VERSION 5.7 ;
  NOWIREEXTENSIONATPIN ON ;
  DIVIDERCHAR "/" ;
  BUSBITCHARS "[]" ;
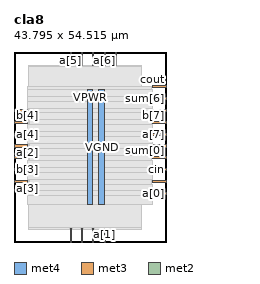
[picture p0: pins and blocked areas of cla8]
MACRO cla8
  CLASS BLOCK ;
  FOREIGN cla8 ;
  ORIGIN 0.000 0.000 ;
  SIZE 43.795 BY 54.515 ;
  PIN VGND
    DIRECTION INOUT ;
    USE GROUND ;
    PORT
      LAYER met4 ;
        RECT 24.340 10.640 25.940 43.760 ;
    END
  END VGND
  PIN VPWR
    DIRECTION INOUT ;
    USE POWER ;
    PORT
      LAYER met4 ;
        RECT 21.040 10.640 22.640 43.760 ;
    END
  END VPWR
  PIN a[0]
    DIRECTION INPUT ;
    USE SIGNAL ;
    ANTENNAGATEAREA 0.196500 ;
    PORT
      LAYER met3 ;
        RECT 39.795 13.640 43.795 14.240 ;
    END
  END a[0]
  PIN a[1]
    DIRECTION INPUT ;
    USE SIGNAL ;
    ANTENNAGATEAREA 0.196500 ;
    PORT
      LAYER met2 ;
        RECT 25.850 0.000 26.130 4.000 ;
    END
  END a[1]
  PIN a[2]
    DIRECTION INPUT ;
    USE SIGNAL ;
    ANTENNAGATEAREA 0.196500 ;
    PORT
      LAYER met3 ;
        RECT 0.000 27.240 4.000 27.840 ;
    END
  END a[2]
  PIN a[3]
    DIRECTION INPUT ;
    USE SIGNAL ;
    ANTENNAGATEAREA 0.196500 ;
    PORT
      LAYER met3 ;
        RECT 0.000 17.040 4.000 17.640 ;
    END
  END a[3]
  PIN a[4]
    DIRECTION INPUT ;
    USE SIGNAL ;
    ANTENNAGATEAREA 0.196500 ;
    PORT
      LAYER met3 ;
        RECT 0.000 30.640 4.000 31.240 ;
    END
  END a[4]
  PIN a[5]
    DIRECTION INPUT ;
    USE SIGNAL ;
    ANTENNAGATEAREA 0.196500 ;
    PORT
      LAYER met2 ;
        RECT 16.190 50.515 16.470 54.515 ;
    END
  END a[5]
  PIN a[6]
    DIRECTION INPUT ;
    USE SIGNAL ;
    ANTENNAGATEAREA 0.196500 ;
    PORT
      LAYER met2 ;
        RECT 25.850 50.515 26.130 54.515 ;
    END
  END a[6]
  PIN a[7]
    DIRECTION INPUT ;
    USE SIGNAL ;
    ANTENNAGATEAREA 0.196500 ;
    PORT
      LAYER met3 ;
        RECT 39.795 30.640 43.795 31.240 ;
    END
  END a[7]
  PIN b[0]
    DIRECTION INPUT ;
    USE SIGNAL ;
    ANTENNAGATEAREA 0.196500 ;
    PORT
      LAYER met3 ;
        RECT 39.795 17.040 43.795 17.640 ;
    END
  END b[0]
  PIN b[1]
    DIRECTION INPUT ;
    USE SIGNAL ;
    ANTENNAGATEAREA 0.196500 ;
    PORT
      LAYER met2 ;
        RECT 22.630 0.000 22.910 4.000 ;
    END
  END b[1]
  PIN b[2]
    DIRECTION INPUT ;
    USE SIGNAL ;
    ANTENNAGATEAREA 0.196500 ;
    PORT
      LAYER met3 ;
        RECT 0.000 23.840 4.000 24.440 ;
    END
  END b[2]
  PIN b[3]
    DIRECTION INPUT ;
    USE SIGNAL ;
    ANTENNAGATEAREA 0.196500 ;
    PORT
      LAYER met3 ;
        RECT 0.000 20.440 4.000 21.040 ;
    END
  END b[3]
  PIN b[4]
    DIRECTION INPUT ;
    USE SIGNAL ;
    ANTENNAGATEAREA 0.196500 ;
    PORT
      LAYER met3 ;
        RECT 0.000 34.040 4.000 34.640 ;
    END
  END b[4]
  PIN b[5]
    DIRECTION INPUT ;
    USE SIGNAL ;
    ANTENNAGATEAREA 0.196500 ;
    PORT
      LAYER met2 ;
        RECT 19.410 50.515 19.690 54.515 ;
    END
  END b[5]
  PIN b[6]
    DIRECTION INPUT ;
    USE SIGNAL ;
    ANTENNAGATEAREA 0.196500 ;
    PORT
      LAYER met2 ;
        RECT 29.070 50.515 29.350 54.515 ;
    END
  END b[6]
  PIN b[7]
    DIRECTION INPUT ;
    USE SIGNAL ;
    ANTENNAGATEAREA 0.196500 ;
    PORT
      LAYER met3 ;
        RECT 39.795 34.040 43.795 34.640 ;
    END
  END b[7]
  PIN cin
    DIRECTION INPUT ;
    USE SIGNAL ;
    ANTENNAGATEAREA 0.196500 ;
    PORT
      LAYER met3 ;
        RECT 39.795 20.440 43.795 21.040 ;
    END
  END cin
  PIN cout
    DIRECTION OUTPUT ;
    USE SIGNAL ;
    ANTENNADIFFAREA 0.445500 ;
    PORT
      LAYER met3 ;
        RECT 39.795 44.240 43.795 44.840 ;
    END
  END cout
  PIN sum[0]
    DIRECTION OUTPUT ;
    USE SIGNAL ;
    ANTENNADIFFAREA 0.445500 ;
    PORT
      LAYER met3 ;
        RECT 39.795 23.840 43.795 24.440 ;
    END
  END sum[0]
  PIN sum[1]
    DIRECTION OUTPUT ;
    USE SIGNAL ;
    ANTENNADIFFAREA 0.445500 ;
    PORT
      LAYER met3 ;
        RECT 39.795 27.240 43.795 27.840 ;
    END
  END sum[1]
  PIN sum[2]
    DIRECTION OUTPUT ;
    USE SIGNAL ;
    ANTENNADIFFAREA 0.445500 ;
    PORT
      LAYER met2 ;
        RECT 19.410 0.000 19.690 4.000 ;
    END
  END sum[2]
  PIN sum[3]
    DIRECTION OUTPUT ;
    USE SIGNAL ;
    ANTENNADIFFAREA 0.445500 ;
    PORT
      LAYER met2 ;
        RECT 16.190 0.000 16.470 4.000 ;
    END
  END sum[3]
  PIN sum[4]
    DIRECTION OUTPUT ;
    USE SIGNAL ;
    ANTENNADIFFAREA 0.445500 ;
    PORT
      LAYER met3 ;
        RECT 0.000 37.440 4.000 38.040 ;
    END
  END sum[4]
  PIN sum[5]
    DIRECTION OUTPUT ;
    USE SIGNAL ;
    ANTENNADIFFAREA 0.445500 ;
    PORT
      LAYER met2 ;
        RECT 22.630 50.515 22.910 54.515 ;
    END
  END sum[5]
  PIN sum[6]
    DIRECTION OUTPUT ;
    USE SIGNAL ;
    ANTENNADIFFAREA 0.445500 ;
    PORT
      LAYER met3 ;
        RECT 39.795 40.840 43.795 41.440 ;
    END
  END sum[6]
  PIN sum[7]
    DIRECTION OUTPUT ;
    USE SIGNAL ;
    ANTENNADIFFAREA 0.445500 ;
    PORT
      LAYER met3 ;
        RECT 39.795 37.440 43.795 38.040 ;
    END
  END sum[7]
  OBS
      LAYER nwell ;
        RECT 5.330 10.795 38.370 43.605 ;
      LAYER li1 ;
        RECT 5.520 10.795 38.180 43.605 ;
      LAYER met1 ;
        RECT 4.210 10.640 38.180 43.760 ;
      LAYER met2 ;
        RECT 4.230 50.235 15.910 50.515 ;
        RECT 16.750 50.235 19.130 50.515 ;
        RECT 19.970 50.235 22.350 50.515 ;
        RECT 23.190 50.235 25.570 50.515 ;
        RECT 26.410 50.235 28.790 50.515 ;
        RECT 29.630 50.235 36.710 50.515 ;
        RECT 4.230 4.280 36.710 50.235 ;
        RECT 4.230 3.670 15.910 4.280 ;
        RECT 16.750 3.670 19.130 4.280 ;
        RECT 19.970 3.670 22.350 4.280 ;
        RECT 23.190 3.670 25.570 4.280 ;
        RECT 26.410 3.670 36.710 4.280 ;
      LAYER met3 ;
        RECT 3.990 43.840 39.395 44.705 ;
        RECT 3.990 41.840 39.795 43.840 ;
        RECT 3.990 40.440 39.395 41.840 ;
        RECT 3.990 38.440 39.795 40.440 ;
        RECT 4.400 37.040 39.395 38.440 ;
        RECT 3.990 35.040 39.795 37.040 ;
        RECT 4.400 33.640 39.395 35.040 ;
        RECT 3.990 31.640 39.795 33.640 ;
        RECT 4.400 30.240 39.395 31.640 ;
        RECT 3.990 28.240 39.795 30.240 ;
        RECT 4.400 26.840 39.395 28.240 ;
        RECT 3.990 24.840 39.795 26.840 ;
        RECT 4.400 23.440 39.395 24.840 ;
        RECT 3.990 21.440 39.795 23.440 ;
        RECT 4.400 20.040 39.395 21.440 ;
        RECT 3.990 18.040 39.795 20.040 ;
        RECT 4.400 16.640 39.395 18.040 ;
        RECT 3.990 14.640 39.795 16.640 ;
        RECT 3.990 13.240 39.395 14.640 ;
        RECT 3.990 10.715 39.795 13.240 ;
  END
END cla8
END LIBRARY

